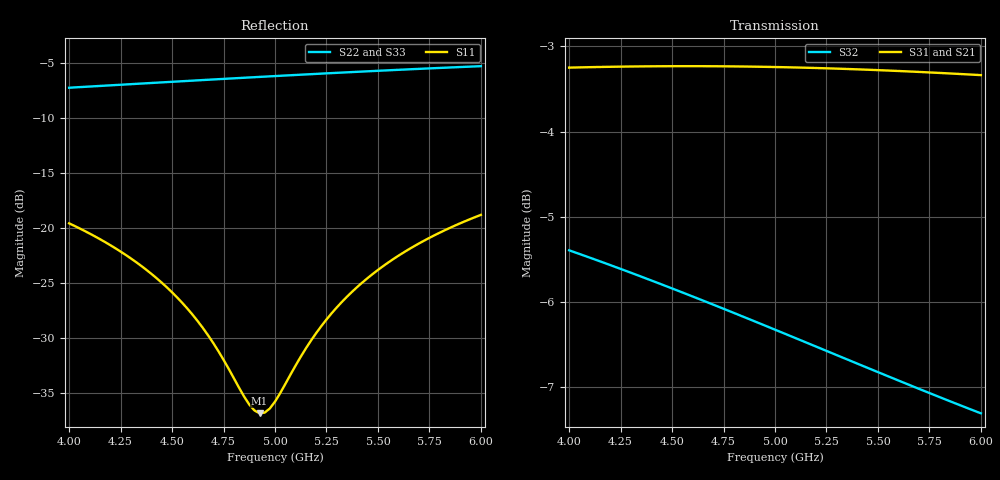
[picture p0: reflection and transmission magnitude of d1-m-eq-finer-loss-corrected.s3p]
! yapnr Order 0 prediction d1-m-eq-finer: predictions/D1/runs/d1-star/finer.s3p, loss-corrected
! substrate M-eq; coupon model OSHPARK-4L-FR408HR; correction: ratio (port line)
! |S21|, |S31| (and S12, S13) scaled, phases kept; 50 ohm, e^(+jwt)
# GHz S RI R 50
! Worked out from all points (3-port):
!   81 points, 4 GHz to 6 GHz, reference 50 ohm
!   strongest paths, dB at 4 GHz, 4.5 GHz, 5 GHz, 5.5 GHz, 6 GHz:
!     S31: -3.2, -3.2, -3.2, -3.3, -3.3
!     S21: -3.2, -3.2, -3.2, -3.3, -3.3
!     S32: -5.4, -5.8, -6.3, -6.8, -7.3
!   lowest |S11| = -36.9 dB at 4.925 GHz (marker M1), VSWR 1.03, Z = 48.6 + j0.314 ohm
!   |S11| at or under -10 dB: start of sweep to end of sweep
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4  -0.0347 0.0991  -0.2263 -0.6496  -0.2263 -0.6496
   -0.2264 -0.6496  0.3198 0.2938  -0.4013 -0.3575
   -0.2264 -0.6496  -0.4013 -0.3575  0.3198 0.2938
4.5  -0.0146 0.0489  -0.3802 -0.5749  -0.3802 -0.5749
     -0.3803 -0.5748  0.4142 0.2047  -0.4604 -0.2204
     -0.3803 -0.5748  -0.4604 -0.2204  0.4142 0.2047
4.65  -0.0125 0.0327  -0.4222 -0.5448  -0.4222 -0.5448
      -0.4222 -0.5447  0.4379 0.1724  -0.4692 -0.1788
      -0.4222 -0.5447  -0.4692 -0.1788  0.4379 0.1724
4.875  -0.0132 0.00853  -0.4805 -0.4937  -0.4805 -0.4937
       -0.4805 -0.4936  0.4684 0.1197  -0.4754 -0.1175
       -0.4805 -0.4936  -0.4754 -0.1175  0.4684 0.1197
4.925  -0.014 0.00322  -0.4926 -0.4814  -0.4926 -0.4814
       -0.4926 -0.4813  0.4743 0.1074  -0.4757 -0.1041
       -0.4926 -0.4813  -0.4757 -0.1041  0.4743 0.1074
5  -0.0156 -0.00465  -0.5101 -0.4624  -0.5101 -0.4624
   -0.5101 -0.4624  0.4826 0.0885  -0.4754 -0.0844
   -0.5101 -0.4624  -0.4754 -0.0844  0.4826 0.0885
5.2  -0.0221 -0.0249  -0.553 -0.4086  -0.553 -0.4086
     -0.553 -0.4086  0.5006 0.0363  -0.4707 -0.0333
     -0.553 -0.4086  -0.4707 -0.0333  0.5006 0.0363
5.4  -0.0319 -0.0435  -0.5899 -0.3508  -0.5899 -0.3508
     -0.5899 -0.3508  0.5127 -0.0182  -0.4609 0.0149
     -0.5899 -0.3508  -0.4609 0.0149  0.5127 -0.0182
5.675  -0.0502 -0.0655  -0.6303 -0.2662  -0.6303 -0.2662
       -0.6303 -0.2661  0.5192 -0.0953  -0.4404 0.0759
       -0.6303 -0.2661  -0.4404 0.0759  0.5192 -0.0953
6  -0.0776 -0.0845  -0.6618 -0.1609  -0.6618 -0.1609
   -0.6617 -0.1608  0.5111 -0.1871  -0.4081 0.1393
   -0.6617 -0.1608  -0.4081 0.1393  0.5111 -0.1871
